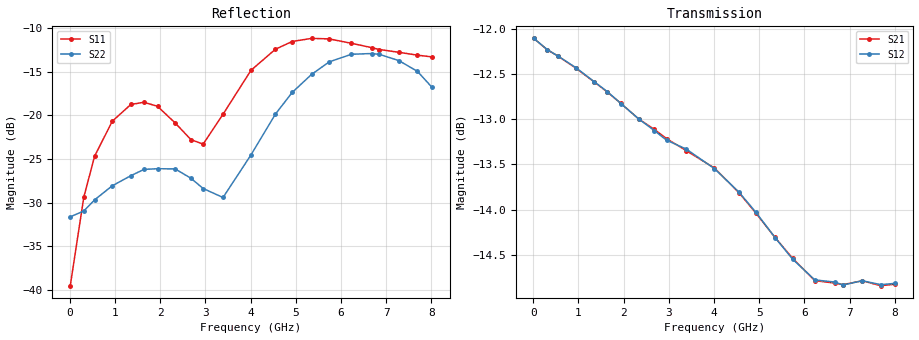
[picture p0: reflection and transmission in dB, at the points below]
!Agilent Technologies,E5071B,MY42404982,A.09.10
!Date: Mon Oct 20 18:08:03 2025
!Data & Calibration Information:
!Freq	S11:SOLT2(ON)	S21:SOLT2(ON)	S12:SOLT2(ON)	S22:SOLT2(ON)
# Hz S RI R 50
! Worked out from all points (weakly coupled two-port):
!   801 points, 10 MHz to 8.01 GHz, reference 50 ohm
!   highest |S21| = -12.10 dB at 10 MHz (marker M1); lowest = -14.8 dB at 7.69 GHz (marker M2)
!   lowest |S11| = -39.5 dB at 10 MHz (marker M3), VSWR 1.02, Z = 49 - j0.178 ohm
!   |S11| at or under -10 dB: start of sweep to end of sweep
!   |S22| runs from -31.7 to -12.8 dB; largest |S21 - S12| = 0.0028
!   S11 on the Smith chart (normalised r, x): 10 MHz: 0.98, -0.00; 4.55 GHz: 0.62, +0.10; 5.74 GHz: 1.13, +0.59; 6.85 GHz: 1.36, -0.45; 8.01 GHz: 0.66, -0.11
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1e7  -0.0104 -0.00182  0.2481 -0.00542  0.2481 -0.00561  0.0262 -0.000953
3.1e8  -0.0209 -0.0269  0.2061 -0.1317  0.2061 -0.1318  0.0233 -0.0161
5.5e8  -0.0426 -0.0402  0.1308 -0.2043  0.1307 -0.2044  0.0146 -0.0294
9.4e8  -0.088 -0.0291  -0.0312 -0.2369  -0.0309 -0.2371  -0.0154 -0.0364
1.35e9  -0.1131 0.0242  -0.1783 -0.1527  -0.1783 -0.1528  -0.0431 -0.0134
1.64e9  -0.0965 0.0698  -0.2275 -0.0442  -0.2276 -0.0443  -0.0472 0.0133
1.94e9  -0.0526 0.0999  -0.2154 0.076  -0.2154 0.0759  -0.0315 0.0382
2.33e9  0.0192 0.0886  -0.1165 0.1913  -0.1165 0.1913  0.00271 0.0493
2.68e9  0.0631 0.0361  0.0144 0.2205  0.0141 0.2202  0.0302 0.0315
2.95e9  0.0647 -0.0224  0.1115 0.1878  0.1113 0.1874  0.0372 0.0083
3.39e9  0.00283 -0.1016  0.2074 0.0568  0.2078 0.057  0.0181 -0.0286
4.01e9  -0.1614 -0.0837  0.1436 -0.1537  0.1438 -0.1533  -0.0508 -0.031
4.55e9  -0.2277 0.0759  -0.0401 -0.1999  -0.0398 -0.2001  -0.094 0.0394
4.92e9  -0.1744 0.2005  -0.1487 -0.1318  -0.1481 -0.1328  -0.0792 0.11
5.35e9  -0.0275 0.2756  -0.1925 0.00397  -0.1925 0.00278  -0.00347 0.1721
5.74e9  0.1271 0.2439  -0.1449 0.119  -0.1447 0.1189  0.0983 0.1777
6.23e9  0.245 0.0856  -0.0112 0.1819  -0.00868 0.1822  0.2055 0.0903
6.68e9  0.225 -0.0971  0.1179 0.1382  0.1184 0.1381  0.2237 -0.0369
6.85e9  0.1826 -0.1543  0.1519 0.099  0.1525 0.0979  0.2076 -0.0846
7.28e9  0.0256 -0.229  0.1798 -0.0295  0.1798 -0.0296  0.1208 -0.1675
7.69e9  -0.1283 -0.181  0.1164 -0.1387  0.1163 -0.1391  0.0136 -0.1787
8.01e9  -0.2004 -0.0829  0.0249 -0.1797  0.0256 -0.1798  -0.0576 -0.1336
